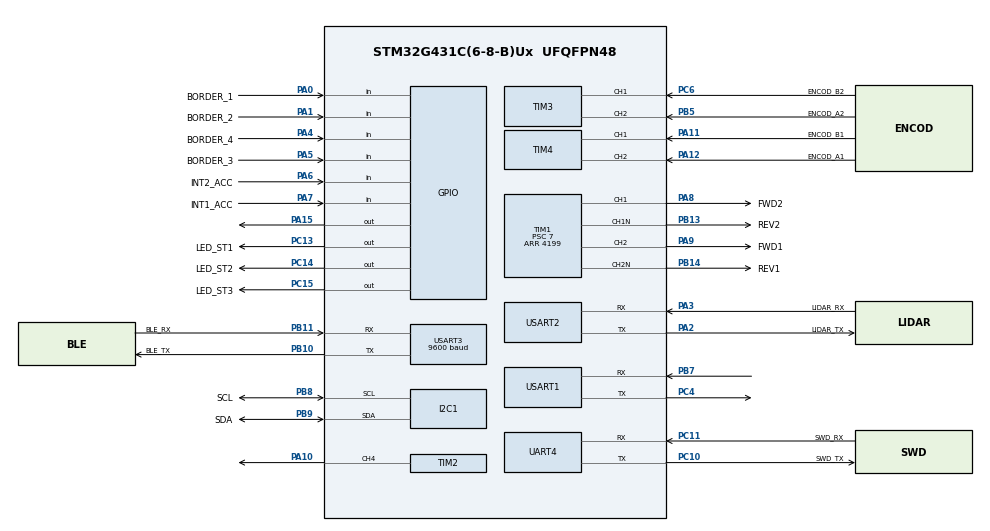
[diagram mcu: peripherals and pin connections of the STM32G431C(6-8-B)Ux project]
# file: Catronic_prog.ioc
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Dma.Request0=USART2_RX
Dma.USART2_RX.0.Direction=DMA_PERIPH_TO_MEMORY
Dma.USART2_RX.0.EventEnable=DISABLE
Dma.USART2_RX.0.Instance=DMA1_Channel1
Dma.USART2_RX.0.MemDataAlignment=DMA_MDATAALIGN_BYTE
Dma.USART2_RX.0.MemInc=DMA_MINC_ENABLE
Dma.USART2_RX.0.Mode=DMA_CIRCULAR
Dma.USART2_RX.0.PeriphDataAlignment=DMA_PDATAALIGN_BYTE
Dma.USART2_RX.0.PeriphInc=DMA_PINC_DISABLE
Dma.USART2_RX.0.Polarity=HAL_DMAMUX_REQ_GEN_RISING
Dma.USART2_RX.0.Priority=DMA_PRIORITY_LOW
Dma.USART2_RX.0.RequestNumber=1
Dma.USART2_RX.0.SignalID=NONE
Dma.USART2_RX.0.SyncEnable=DISABLE
Dma.USART2_RX.0.SyncPolarity=HAL_DMAMUX_SYNC_NO_EVENT
Dma.USART2_RX.0.SyncRequestNumber=1
Dma.USART2_RX.0.SyncSignalID=NONE
FREERTOS.Tasks01=defaultTask,24,128,StartDefaultTask,Default,NULL,Dynamic,NULL,NULL
I2C1.Timing=0x00503D58
Mcu.Family=STM32G4
Mcu.Name=STM32G431C(6-8-B)Ux
Mcu.Package=UFQFPN48
NVIC.DMA1_Channel1_IRQn=true\:5\:0\:false\:false\:true\:true\:false\:true\:true
NVIC.PriorityGroup=NVIC_PRIORITYGROUP_4
NVIC.USART2_IRQn=true\:5\:0\:false\:false\:true\:true\:true\:true\:true
NVIC.USART3_IRQn=true\:5\:0\:false\:false\:true\:true\:true\:true\:true
PA0.GPIO_Label=BORDER_1
PA0.Signal=GPIO_Input
PA1.GPIO_Label=BORDER_2
PA1.Signal=GPIO_Input
PA10.Signal=S_TIM2_CH4
PA11.GPIO_Label=ENCOD_B1
PA11.Signal=S_TIM4_CH1
PA12.GPIO_Label=ENCOD_A1
PA12.Signal=S_TIM4_CH2
PA13.GPIO_Label=SWDIO
PA13.Mode=Trace_Asynchronous_SW
PA13.Signal=SYS_JTMS-SWDIO
PA14.GPIO_Label=SWCLK
PA14.Mode=Trace_Asynchronous_SW
PA14.Signal=SYS_JTCK-SWCLK
PA15.Signal=GPIO_Output
PA2.GPIO_Label=LIDAR_TX
PA2.Mode=Asynchronous
PA2.Signal=USART2_TX
PA3.GPIO_Label=LIDAR_RX
PA3.Mode=Asynchronous
PA3.Signal=USART2_RX
PA4.GPIO_Label=BORDER_4
PA4.Signal=GPIO_Input
PA5.GPIO_Label=BORDER_3
PA5.GPIO_PuPd=GPIO_NOPULL
PA5.Signal=GPIO_Input
PA6.GPIO_Label=INT2_ACC
PA6.Signal=GPIO_Input
PA7.GPIO_Label=INT1_ACC
PA7.Signal=GPIO_Input
PA8.GPIO_Label=FWD2
PA8.Signal=S_TIM1_CH1
PA9.GPIO_Label=FWD1
PA9.Signal=S_TIM1_CH2
PB10.GPIO_Label=BLE_TX
PB10.Mode=Asynchronous
PB10.Signal=USART3_TX
PB11.GPIO_Label=BLE_RX
PB11.Mode=Asynchronous
PB11.Signal=USART3_RX
PB13.GPIO_Label=REV2
PB13.Mode=PWM Generation1 CH1 CH1N
PB13.Signal=TIM1_CH1N
PB14.GPIO_Label=REV1
PB14.Mode=PWM Generation2 CH2 CH2N
PB14.Signal=TIM1_CH2N
PB3.GPIO_Label=SWO
PB3.Mode=Trace_Asynchronous_SW
PB3.Signal=SYS_JTDO-SWO
PB5.GPIO_Label=ENCOD_A2
PB5.Signal=S_TIM3_CH2
PB7.Mode=Asynchronous
PB7.Signal=USART1_RX
PB8-BOOT0.GPIO_Label=SCL
PB8-BOOT0.Mode=I2C
PB8-BOOT0.Signal=I2C1_SCL
PB9.GPIO_Label=SDA
PB9.Mode=I2C
PB9.Signal=I2C1_SDA
PC10.GPIO_Label=SWD_TX
PC10.Mode=Asynchronous
PC10.Signal=UART4_TX
PC11.GPIO_Label=SWD_RX
PC11.Mode=Asynchronous
PC11.Signal=UART4_RX
PC13.GPIO_Label=LED_ST1
PC13.Signal=GPIO_Output
PC14-OSC32_IN.GPIO_Label=LED_ST2
PC14-OSC32_IN.Signal=GPIO_Output
PC15-OSC32_OUT.GPIO_Label=LED_ST3
PC15-OSC32_OUT.Signal=GPIO_Output
PC4.Mode=Asynchronous
PC4.Signal=USART1_TX
PC6.GPIO_Label=ENCOD_B2
PC6.Signal=S_TIM3_CH1
ProjectManager.HeapSize=0x200
ProjectManager.StackSize=0x400
ProjectManager.TargetToolchain=STM32CubeIDE
RCC.AHBFreq_Value=16000000
RCC.APB1Freq_Value=16000000
RCC.APB1TimFreq_Value=16000000
RCC.APB2Freq_Value=16000000
RCC.APB2TimFreq_Value=16000000
RCC.CortexFreq_Value=16000000
RCC.EXTERNAL_CLOCK_VALUE=12288000
RCC.HCLKFreq_Value=16000000
RCC.HSE_VALUE=8000000
RCC.HSI48_VALUE=48000000
RCC.HSI_VALUE=16000000
RCC.LSE_VALUE=32768
RCC.SYSCLKFreq_VALUE=16000000
RCC.USBFreq_Value=64000000
RCC.VCOOutputFreq_Value=128000000
SH.S_TIM1_CH1.0=TIM1_CH1,PWM Generation1 CH1 CH1N
SH.S_TIM1_CH2.0=TIM1_CH2,PWM Generation2 CH2 CH2N
SH.S_TIM2_CH4.0=TIM2_CH4,Output Compare4 CH4
SH.S_TIM3_CH1.0=TIM3_CH1,Encoder_Interface
SH.S_TIM3_CH2.0=TIM3_CH2,Encoder_Interface
SH.S_TIM4_CH1.0=TIM4_CH1,Encoder_Interface
SH.S_TIM4_CH2.0=TIM4_CH2,Encoder_Interface
TIM1.Channel-PWM\ Generation1\ CH1\ CH1N=TIM_CHANNEL_1
TIM1.Channel-PWM\ Generation2\ CH2\ CH2N=TIM_CHANNEL_2
TIM1.PeriodNoDither=4199
TIM1.Prescaler=7
TIM2.AutoReloadPreload=TIM_AUTORELOAD_PRELOAD_ENABLE
TIM2.Channel-Output\ Compare4\ CH4=TIM_CHANNEL_4
TIM2.OCMode_4=TIM_OCMODE_TIMING
TIM2.PeriodNoDither=799
TIM2.PulseNoDither_4=400
TIM3.IC1Filter=4
TIM3.IC2Filter=4
TIM4.IC2Filter=4
USART1.VirtualMode-Asynchronous=VM_ASYNC
USART2.VirtualMode-Asynchronous=VM_ASYNC
USART3.BaudRate=9600
USART3.VirtualMode-Asynchronous=VM_ASYNC
VP_FREERTOS_VS_CMSIS_V2.Mode=CMSIS_V2
VP_SYS_VS_DBSignals.Mode=DisableDeadBatterySignals
VP_TIM2_VS_ClockSourceINT.Mode=Internal
board=custom

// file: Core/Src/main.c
/* USER CODE BEGIN Header */
/**
 ******************************************************************************
 * @file           : main.c
 * @brief          : Main program body
 ******************************************************************************
 * @attention
 *
 * Copyright (c) 2025 STMicroelectronics.
 * All rights reserved.
 *
 * This software is licensed under terms that can be found in the LICENSE file
 * in the root directory of this software component.
 * If no LICENSE file comes with this software, it is provided AS-IS.
 *
 ******************************************************************************
 */
/* USER CODE END Header */
#include "main.h"
#include "cmsis_os.h"
#include "dma.h"
#include "i2c.h"
#include "tim.h"
#include "usart.h"
#include "gpio.h"

/* USER CODE BEGIN Includes */
#include "MoteurPWM.h"
#include "drv_bt.h"
#include "ADXL343_driver.h"
#include "driver_LIDAR.h"
#include "border_sensors.h"
#include "robot_logic.h"
#include <stdio.h>
/* USER CODE END Includes */

/* USER CODE BEGIN PV */
Moteur_HandleTypeDef moteurD;
Moteur_HandleTypeDef moteurG;
h_Robot hrob;

SemaphoreHandle_t mutexSensors;

uint8_t lidar_dma_buffer[64]; // Buffer circulaire pour le DMA
h_YLIDARX2_t hlidar;          // Structure de contrôle LIDAR
/* USER CODE END PV */

void SystemClock_Config(void);
void MX_FREERTOS_Init(void);

/* USER CODE BEGIN 0 */
int __io_putchar(int ch)
{
	HAL_UART_Transmit(&huart4, (uint8_t*)&ch, 1, HAL_MAX_DELAY);
	return ch;
}

/* USER CODE END 0 */

int main(void)
{

	/* MCU Configuration--------------------------------------------------------*/

	/* Reset of all peripherals, Initializes the Flash interface and the Systick. */
	HAL_Init();

	/* Configure the system clock */
	SystemClock_Config();

	/* Initialize all configured peripherals */
	MX_GPIO_Init();
	MX_DMA_Init();
	MX_I2C1_Init();
	MX_TIM3_Init();
	MX_TIM4_Init();
	MX_TIM1_Init();
	MX_UART4_Init();
	MX_USART2_UART_Init();
	MX_USART3_UART_Init();
	MX_USART1_UART_Init();
	MX_TIM2_Init();
	/* USER CODE BEGIN 2 */

	//Initialisation du Bluetooth
	BT_Init();
	BT_SendString("BLE Ready\r\n");

	YLIDAR_Init(&hlidar);
	HAL_UART_Receive_DMA(&huart2, lidar_dma_buffer, sizeof(lidar_dma_buffer));// Démarre la réception DMA en mode circulaire
	HAL_GPIO_WritePin(GPIOA, GPIO_PIN_10, GPIO_PIN_RESET);

	Moteur_init(&moteurD, &htim1, TIM_CHANNEL_1);
	Moteur_init(&moteurG, &htim1, TIM_CHANNEL_2);

	Robot_Init(&hrob, &moteurD, &moteurG);
	printf("Robot Init OK\r\n");

	mutexSensors = xSemaphoreCreateMutex();
	if (mutexSensors == NULL)
	{
		printf("Erreur Mutex !\r\n");
		while(1);
	}
	//TEST tasks
	xTaskCreate(BluetoothTask, "BT", 128, NULL, 5, NULL);
	xTaskCreate(ShockTask,     "Shock", 128, NULL, 4, NULL);
	xTaskCreate(BorderTask,    "Border", 128, NULL, 3, NULL);
	xTaskCreate(RobotModeTask, "Mode", 128, NULL, 2, NULL);

	/* USER CODE END 2 */

	/* Init scheduler */
	osKernelInitialize();

	/* Call init function for freertos objects (in cmsis_os2.c) */
	MX_FREERTOS_Init();

	/* Start scheduler */
	osKernelStart();

	/* We should never get here as control is now taken by the scheduler */

	/* Infinite loop */
	/* USER CODE BEGIN WHILE */
	vTaskStartScheduler();
	printf("Taches FreeRTOS creees.\r\n");
	while (1)
	{

		/* USER CODE END WHILE */

	}
}

void SystemClock_Config(void)
{
	RCC_OscInitTypeDef RCC_OscInitStruct = {0};
	RCC_ClkInitTypeDef RCC_ClkInitStruct = {0};

	/** Configure the main internal regulator output voltage
	 */
	HAL_PWREx_ControlVoltageScaling(PWR_REGULATOR_VOLTAGE_SCALE1_BOOST);

	/** Initializes the RCC Oscillators according to the specified parameters
	 * in the RCC_OscInitTypeDef structure.
	 */
	RCC_OscInitStruct.OscillatorType = RCC_OSCILLATORTYPE_HSI;
	RCC_OscInitStruct.HSIState = RCC_HSI_ON;
	RCC_OscInitStruct.HSICalibrationValue = RCC_HSICALIBRATION_DEFAULT;
	RCC_OscInitStruct.PLL.PLLState = RCC_PLL_ON;
	RCC_OscInitStruct.PLL.PLLSource = RCC_PLLSOURCE_HSI;
	RCC_OscInitStruct.PLL.PLLM = RCC_PLLM_DIV4;
	RCC_OscInitStruct.PLL.PLLN = 85;
	RCC_OscInitStruct.PLL.PLLP = RCC_PLLP_DIV2;
	RCC_OscInitStruct.PLL.PLLQ = RCC_PLLQ_DIV2;
	RCC_OscInitStruct.PLL.PLLR = RCC_PLLR_DIV2;
	if (HAL_RCC_OscConfig(&RCC_OscInitStruct) != HAL_OK)
	{
		Error_Handler();
	}

	/** Initializes the CPU, AHB and APB buses clocks
	 */
	RCC_ClkInitStruct.ClockType = RCC_CLOCKTYPE_HCLK|RCC_CLOCKTYPE_SYSCLK
			|RCC_CLOCKTYPE_PCLK1|RCC_CLOCKTYPE_PCLK2;
	RCC_ClkInitStruct.SYSCLKSource = RCC_SYSCLKSOURCE_PLLCLK;
	RCC_ClkInitStruct.AHBCLKDivider = RCC_SYSCLK_DIV1;
	RCC_ClkInitStruct.APB1CLKDivider = RCC_HCLK_DIV1;
	RCC_ClkInitStruct.APB2CLKDivider = RCC_HCLK_DIV1;

	if (HAL_RCC_ClockConfig(&RCC_ClkInitStruct, FLASH_LATENCY_4) != HAL_OK)
	{
		Error_Handler();
	}
}

/* USER CODE BEGIN 4 */
void HAL_UART_RxHalfCpltCallback(UART_HandleTypeDef *huart) {
	if (huart->Instance == USART2)
		YLIDAR_PushBytes(lidar_dma_buffer, 32);
}

void HAL_UART_RxCpltCallback(UART_HandleTypeDef *huart) {
	if (huart->Instance == USART3) { // Bluetooth
		BT_UART_RxCpltCallback(BT_rxByte);
	}
	if (huart->Instance == USART2)
		YLIDAR_PushBytes(lidar_dma_buffer + 32, 32);
}
/* USER CODE END 4 */

void Error_Handler(void)
{
	__disable_irq();
	while (1)
	{
	}
}
